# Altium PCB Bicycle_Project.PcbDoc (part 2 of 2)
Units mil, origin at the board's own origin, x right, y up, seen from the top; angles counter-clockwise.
Board outline 2480.32 x 3188.98 mil, 2 copper layers (Top Layer, Bottom Layer), stack 35.085 mil thick; 108 components, 95 nets, 359 pads, 124 vias.

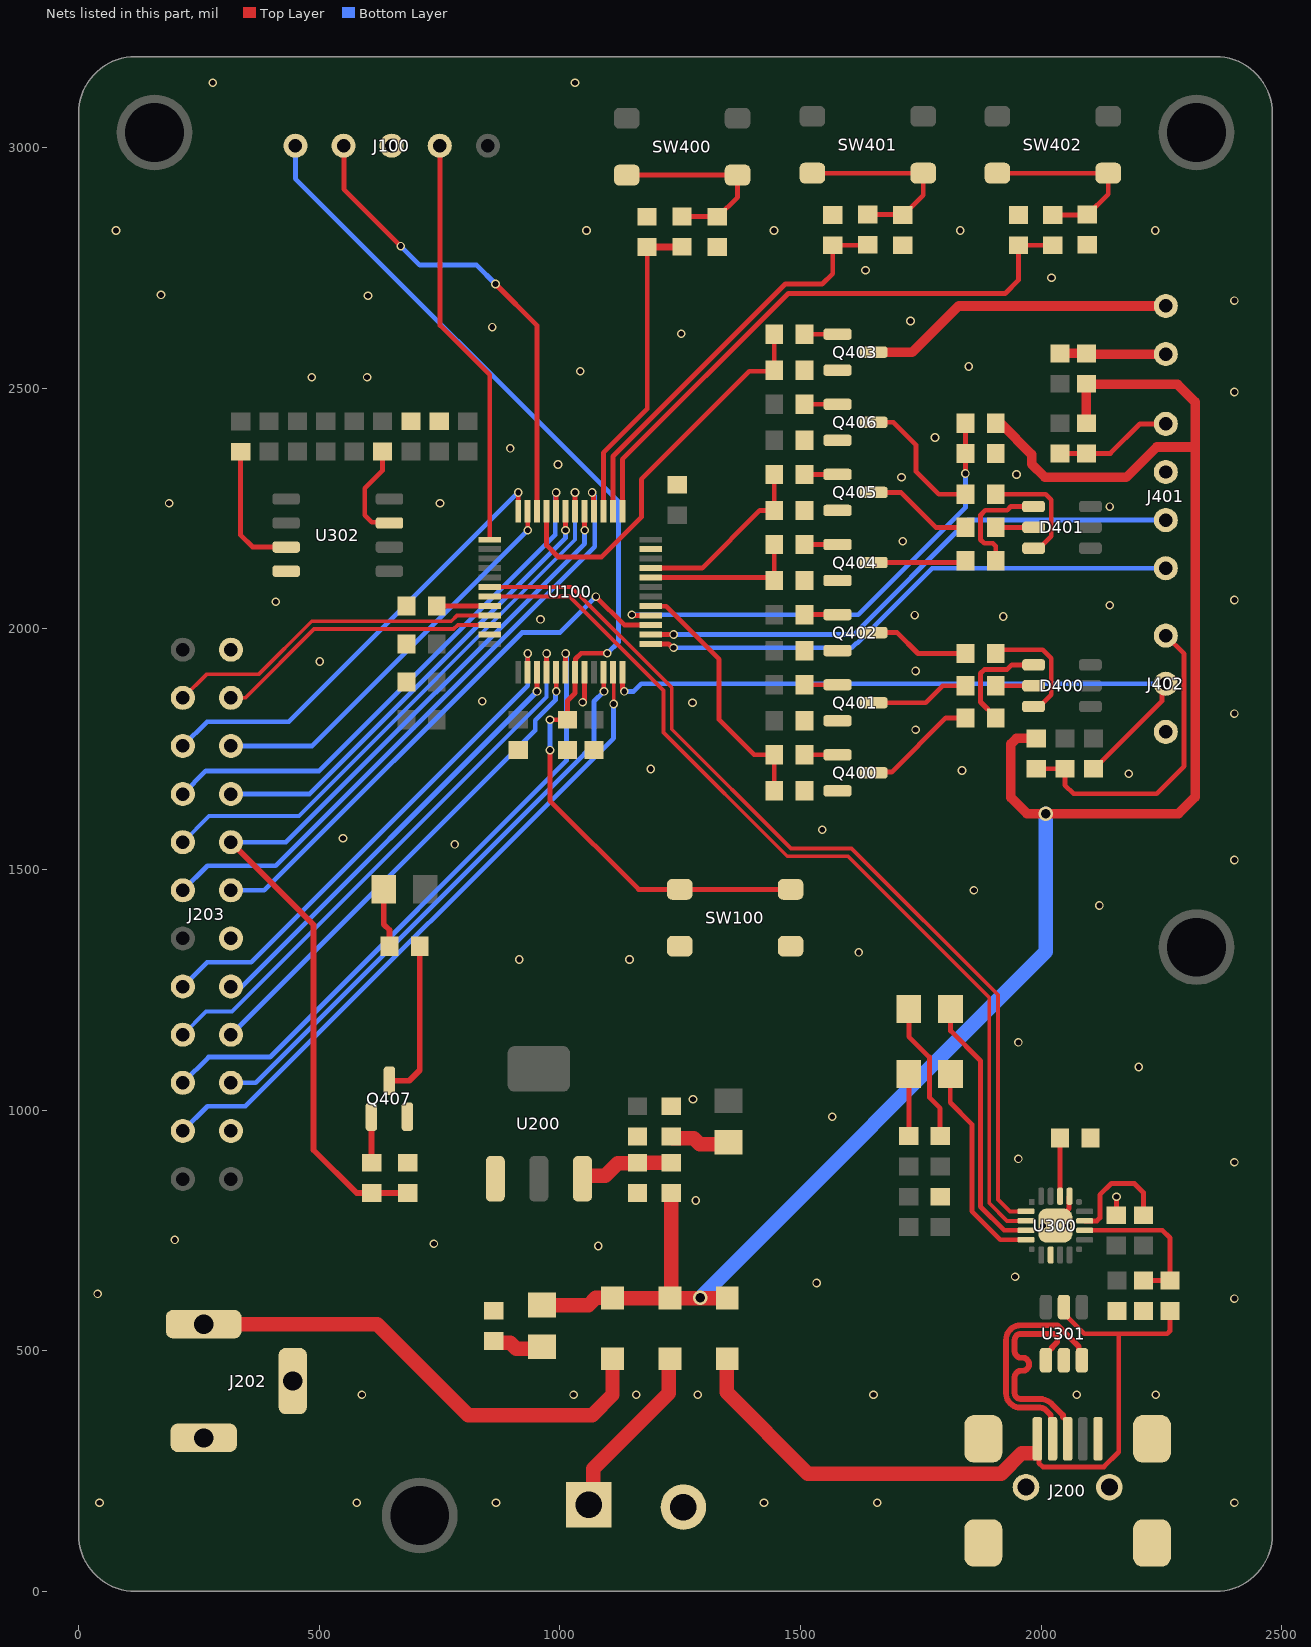
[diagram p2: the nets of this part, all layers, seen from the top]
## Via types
v1: diameter 18, hole 12, Top Layer to Bottom Layer, tented both sides, 122 vias
v2: diameter 30, hole 20, Top Layer to Bottom Layer, tented both sides, 2 vias

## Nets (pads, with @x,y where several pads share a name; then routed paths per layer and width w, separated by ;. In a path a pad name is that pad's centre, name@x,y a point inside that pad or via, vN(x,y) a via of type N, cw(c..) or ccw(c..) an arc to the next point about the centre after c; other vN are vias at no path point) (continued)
G_TEMP_LED: R415.1 R418.2 U100.21 | length 380.9
  Top Layer w10: U100.21@1188.86,2126.26 1295.55,2126.26 1415.26,2245.96 R418.2@1445.39,2245.96 R415.1@1445.39,2320.77
GND: C100.2 C101.2 C102.2 C103.2 C104.2 C105.2 C210.2 C211.2 C300.2 C301.2 C302.2 C303.2 C304.2 C400.1 C401.1 C402.1 J100.3 J200.0 J200.5 J201.2 J202.2 J202.3 J203.3 J203.11 J203.23 J401.2 J402.3 Q400.2 Q401.2 Q402.2 Q403.2 Q404.2 Q405.2 Q406.2 Q407.2 R100.2 R102.1 R200.1 R201.1 R301.2 R305.1 R406.1 R407.1 R408.1 R410.1 R417.1 R418.1 R419.1 R423.1 R424.1 R425.1 R429.1 SW100.2 U100.8 U100.23 U100.47 U200.1 U300.3 U300.12 U300.21 U301.2 U302.4 | length 175.5
  Top Layer w10: v1(1047.24,1847.44) 1047.24,1849.61 1051.06,1853.42 U100.8@1051.06,1909.72 ; U300.21@2029.45,760 2029.45,766.88 2058.07,795.5 2058.07,820.12 U300.12@2058.98,821.02 ; C302.2@2156.2,781.66 2156.5,781.95 v1(2156.5,819.88)
  other v1: 43.31,184.06 577.76,184.06 867.13,184.06 1424.21,184.06 1659.45,184.06 2401.57,184.06 588.58,408.46 1028.54,408.46 1158.46,408.46 1286.42,408.46 1651.57,408.46 2073.82,408.46 2238.19,408.46 2401.57,608.27 39.37,618.11 1533.46,640.75 1945.87,653.54 1079.72,717.52 738.19,722.44 199.8,730.32 2003.94,759.84 2055.12,759.84 1282.48,812.01 2401.57,891.73 1952.76,898.62 1565.94,986.22 1276.57,1022.64 2202.76,1089.57 1952.76,1140.75 915.35,1312.99 1144.68,1312.99 1621.06,1327.76 2121.06,1425.2 1860.24,1456.69 2401.57,1519.68 781.5,1552.17 549.21,1564.96 1545.28,1582.68 2182.09,1698.82 1835.63,1705.71 1188.98,1708.66 1739.17,1790.35 2401.57,1823.82 1275.59,1846.46 838.58,1849.41 1739.17,1912.4 500.98,1932.09 959.65,2019.61 1921.26,2025.59 1737.2,2028.54 2142.72,2049.21 409.45,2056.1 2401.57,2060.04 1712.6,2182.09 2142.72,2253.94 187.99,2260.83 750.98,2260.83 1709.65,2314.96 1948.82,2320.87 996.06,2341.54 896.65,2375 1779.53,2397.64 2401.57,2492.13 484.25,2522.64 599.41,2522.64 1042.32,2535.43 1849.41,2545.28 1251.97,2613.19 859.25,2626.97 1728.35,2639.76 2401.57,2682.09 601.38,2691.93 171.26,2693.9 2021.65,2729.33 1634.84,2745.08 77.76,2827.76 1055.12,2827.76 1444.88,2827.76 1831.69,2827.76 2237.2,2827.76 278.54,3134.84 1031.5,3134.84
LOAD: R409.1 R410.2 U100.33 | length 835.6
  Top Layer w10: U100.33@972.32,2244.37 972.39,2244.3 972.39,2173.28 996.06,2149.61 1086.83,2149.61 1169.29,2232.07 1169.29,2311.02 1393.7,2535.43 1443.43,2535.43 R410.2@1445.39,2537.4 R409.1@1445.39,2612.2
MCU_RX: U100.43 U300.18 | length 1952.9
  Top Layer w8: U100.43@854.21,2067.2 1020.21,2067.2 1215.17,1872.24 1215.17,1784.83 1472.44,1527.56 1598.43,1527.56 1892.02,1233.97 1892.02,807.09 1929.26,769.84 U300.18@1968.43,769.84
MCU_TX: U100.42 U300.17 | length 1951.2
  Top Layer w8: U100.42@854.21,2086.89 1023.15,2086.89 1232.28,1877.76 1232.28,1791.34 1480.06,1543.56 1606.05,1543.56 1910.02,1239.59 1910.02,814.54 1935.03,789.53 U300.17@1968.43,789.53
NetC210_1: C210.1 FB200.2 U200.3 | length 199.3
  Top Layer w30: U200.3@1046.93,857.29 1051.54,861.89 1051.54,863.65 1093.96,863.65 1120.11,889.8 1160.35,889.8 C210.1@1161.3,890.75 FB200.2@1231.3,890.75
NetD201_2: D201.2 R200.2 | length 108.5
  Top Layer w30: R200.2@862.8,520.15 866.3,516.65 896.73,516.65 909.45,503.94 958.54,503.94 D201.2@962.8,508.19
NetD204_2: D204.2 R201.2 | length 127.2
  Top Layer w30: R201.2@1231.3,944.88 1234.8,941.38 1278.11,941.38 1290.35,929.13 1346.46,929.13 D204.2@1350.39,933.07
NetD300_1: D300.1 R302.1 | length 129.1
  Top Layer w10: R302.1@1725.08,945.88 D300.1@1725.08,1075
NetD300_2: D300.2 U300.20 | length 441.2
  Top Layer w10: D300.2@1811.69,1075 1811.02,1074.33 1811.02,1015.75 1856.02,970.76 1856.02,789.65 1915.2,730.47 U300.20@1968.43,730.47
NetD301_1: D301.1 R303.1 | length 291
  Top Layer w10: D301.1@1725.08,1210 1725.08,1152.87 1767.72,1110.24 1767.72,1026.3 1790.08,1003.94 R303.1@1790.08,945.88
NetD301_2: D301.2 U300.19 | length 551.3
  Top Layer w10: D301.2@1811.69,1210 1811.69,1164.69 1874.02,1102.36 1874.02,799.21 1922.88,750.35 1968.23,750.35 U300.19@1968.43,750.16
NetD400_1: D400.1 R400.2 | length 223
  Top Layer w10: R400.2@1905.52,1814.96 1905.52,1816.46 1874.01,1847.96 1874.01,1907.27 1882.56,1915.82 1929.4,1915.82 1938.78,1925.2 D400.1@1984.25,1925.2
NetD400_2: D400.2 R401.2 | length 78.7
  Top Layer w10: R401.2@1905.51,1881.89 D400.2@1984.25,1881.89
NetD400_3: D400.3 R402.2 | length 248.4
  Top Layer w10: R402.2@1905.52,1948.82 1913.39,1956.69 2003.11,1956.69 2020.87,1938.93 2020.87,1863.39 1996.06,1838.58 D400.3@1984.25,1838.58
NetD401_1: D401.1 R411.2 | length 235.8
  Top Layer w10: R411.2@1905.52,2141.73 1905.52,2172.05 1899.66,2177.91 1881.63,2177.91 1874.02,2185.52 1874.02,2236.29 1884.25,2246.53 1929.4,2246.53 1937.09,2254.21 D401.1@1984.25,2254.21
NetD401_2: D401.2 R412.2 | length 78.7
  Top Layer w10: R412.2@1905.52,2210.91 D401.2@1984.25,2210.91
NetD401_3: D401.3 R413.2 | length 242.6
  Top Layer w10: R413.2@1905.52,2279.53 2009.3,2279.53 2020.87,2267.95 2020.87,2192.41 1996.06,2167.6 D401.3@1984.25,2167.6
NetD402_2: D402.2 R427.2 | length 123
  Top Layer w12: D402.2@633.86,1458.66 633.86,1385.83 645.67,1374.02 R427.2@645.67,1340.55
NetFB400_2: FB400.2 FB401.2 J400.2 | length 220.6
  Top Layer w20: FB401.2@2039.02,2572.41 FB400.2@2094.02,2572.41 2095.52,2570.91 J400.2@2259.02,2570.91
NetFB402_2: FB402.2 FB404.2 J402.1 | length 659.3
  Top Layer w10: FB402.2@1989.96,1709.41 FB404.2@2049.49,1709.41 2049.49,1675.47 2067.48,1657.48 2240.16,1657.48 2297.02,1714.34 2297.02,1947.91 J402.1@2259.02,1985.91
NetFB403_2: FB403.2 FB405.2 J401.1 | length 245.5
  Top Layer w10: FB405.2@2039.02,2364.41 FB403.2@2094.02,2364.41 2143.93,2364.41 2205.43,2425.91 J401.1@2259.02,2425.91
NetJ400_1: J400.1 Q403.3 | length 647.2
  Top Layer w20: Q403.3@1651.57,2574.8 1732.28,2574.8 1828.39,2670.91 J400.1@2259.02,2670.91
NetQ400_1: Q400.1 R403.2 | length 70.8
  Top Layer w10: R403.2@1508.39,1738.19 1570.87,1738.19 1573.82,1741.14 Q400.1@1576.77,1738.19
NetQ400_3: Q400.3 R400.1 | length 238.2
  Top Layer w10: Q400.3@1651.57,1700.79 1653.12,1702.33 1689.12,1702.33 1801.75,1814.96 R400.1@1842.52,1814.96
NetQ401_1: Q401.1 R404.2 | length 68.4
  Top Layer w10: R404.2@1508.39,1883.86 Q401.1@1576.77,1883.86
NetQ401_3: Q401.3 R401.1 | length 205.6
  Top Layer w10: Q401.3@1651.57,1846.46 1759.84,1846.46 1795.28,1881.89 R401.1@1842.51,1881.89
NetQ402_1: Q402.1 R405.2 | length 69.2
  Top Layer w10: R405.2@1508.39,2029.53 1574.8,2029.53 1575.79,2030.51 Q402.1@1576.77,2029.53
NetQ402_3: Q402.3 R402.1 | length 208.9
  Top Layer w10: Q402.3@1651.57,1992.13 1700.79,1992.13 1744.09,1948.82 R402.1@1842.52,1948.82
NetQ403_1: Q403.1 R409.2 | length 72.6
  Top Layer w10: R409.2@1508.39,2612.2 1573.82,2612.2 1576.77,2609.25 Q403.1@1576.77,2612.2
NetQ404_1: Q404.1 R414.2 | length 68.5
  Top Layer w10: R414.2@1508.39,2175.39 1508.59,2175.2 Q404.1@1576.77,2175.2
NetQ404_3: Q404.3 R411.1 | length 192.6
  Top Layer w10: Q404.3@1651.57,2137.8 1838.58,2137.8 R411.1@1842.52,2141.73
NetQ405_1: Q405.1 R415.2 | length 68.4
  Top Layer w10: R415.2@1508.39,2320.77 1508.49,2320.87 Q405.1@1576.77,2320.87
NetQ405_3: Q405.3 R412.1 | length 221
  Top Layer w10: Q405.3@1651.57,2283.46 1708.66,2283.46 1781.22,2210.91 R412.1@1842.52,2210.91
NetQ406_1: Q406.1 R416.2 | length 68.4
  Top Layer w10: R416.2@1508.39,2466.54 Q406.1@1576.77,2466.54
NetQ406_3: Q406.3 R413.1 | length 285.2
  Top Layer w10: Q406.3@1651.57,2429.13 1692.91,2429.13 1740.16,2381.89 1740.16,2326.77 1787.4,2279.53 R413.1@1842.52,2279.53
NetQ407_1: Q407.1 R428.2 | length 95.9
  Top Layer w12: Q407.1@608.27,986.22 608.27,891.68 R428.2@609.19,890.75
NetQ407_3: Q407.3 R427.1 | length 329.8
  Top Layer w12: Q407.3@645.67,1061.02 687.01,1061.02 708.67,1082.68 R427.1@708.67,1340.55
NetR100_1: R100.1 U100.44 | length 110.2
  Top Layer w10: R100.1@744.1,2047.24 744.37,2047.52 U100.44@854.21,2047.52
NetR300_2: R300.2 R301.1 U300.8 | length 327.6
  Top Layer w10: U300.8@2090.47,750.16 2251.86,750.16 2267.72,734.3 R300.2@2267.72,645.67 R301.1@2212.6,645.67
NetR304_2: R304.2 U300.9 | length 237.2
  Top Layer w10: U300.9@2090.47,769.84 2115.98,769.84 2122.05,775.91 2122.05,823.82 2145.67,847.44 2193.9,847.44 2212.6,828.74 R304.2@2212.6,781.66
NetR305_2: R305.2 U300.13 | length 120.9
  Top Layer w10: U300.13@2039.29,821.02 R305.2@2039.29,941.93
NetR306_1: R306.1 U302.3 | length 278.1
  Top Layer w10: R306.1@336.61,2368.11 336.61,2194.88 361.22,2170.28 430.67,2170.28 U302.3@431.14,2169.8
NetR309_1: R309.1 U302.7 | length 205.4
  Top Layer w10: R309.1@631.5,2368.3 631.5,2329.33 594.49,2292.32 594.49,2236.22 609.25,2221.46 644.06,2221.46 U302.7@645.71,2219.8
NetR420_1: R420.1 R423.2 SW400.1 | length 408.5
  Top Layer w10: SW400.1@1138.78,2942.91 SW400.1@1369.09,2942.91 1369.09,2897.13 1328.27,2856.3 R423.2@1326.77,2856.3 1326.06,2857.01 R420.1@1253.94,2857.01
NetR421_1: R421.1 R424.2 SW401.1 | length 408.5
  Top Layer w10: SW401.1@1524.61,2946.85 SW401.1@1754.92,2946.85 1754.92,2901.06 1714.1,2860.24 R424.2@1712.6,2860.24 1711.89,2860.95 R421.1@1639.76,2860.95
NetR422_1: R422.1 R425.2 SW402.1 | length 407
  Top Layer w10: SW402.1@1909.09,2946.85 SW402.1@2139.41,2946.85 2139.41,2903.11 2097.25,2860.95 R425.2@2095.75,2860.95 2095.04,2860.24 R422.1@2024.25,2860.24
PA0: J203.5 U100.10 | length 1204.9
  Top Layer w10: U100.10@1090.43,1909.72 1091.09,1909.07 1091.09,1870.74 v1(1091.75,1870.08)
  Bottom Layer w10: J203.5@316.54,1056.69 368.14,1056.69 1027.56,1716.12 1027.56,1716.54 1070.87,1759.84 1070.87,1849.2 v1(1091.75,1870.08)
PA1: J203.4 U100.11 | length 1370.6
  Top Layer w8: U100.11@1110.12,1909.72 1111.75,1908.09 1111.75,1844.03 v1(1111.55,1843.83)
  Bottom Layer w10: J203.4@216.54,956.69 267.72,1007.87 346.46,1007.87 1111.55,1772.97 v1(1111.55,1843.83)
PA5: J203.13 U100.15 | length 1149.4
  Top Layer w10: v1(1074.8,2066.93) 1133.58,2008.15 U100.15@1188.86,2008.15
  Bottom Layer w10: J203.13@316.54,1456.69 385.83,1456.69 921.26,1992.13 1000,1992.13 v1(1074.8,2066.93)
PA9: J203.16 U100.30 | length 1212.8
  Top Layer w10: U100.30@1031.38,2244.37 U100.30@1031.38,2244.37 1031.44,2283.41 v1(1031.5,2283.46)
  Bottom Layer w8: J203.16@216.54,1556.69 270.95,1611.1 457.56,1611.1 1031.5,2185.04 v1(1031.5,2283.46)
PA10: J203.17 U100.31 | length 971.1
  Top Layer w10: v1(1011.5,2204.72) 1011.59,2204.82 1011.59,2244.27 U100.31@1011.69,2244.37
  Bottom Layer w10: J203.17@316.54,1656.69 479.53,1656.69 1011.5,2188.66 v1(1011.5,2204.72)
PA11: J203.18 U100.32 | length 1125.1
  Top Layer w10: U100.32@992.01,2244.37 992.07,2244.43 992.07,2283.41 v1(992.13,2283.46)
  Bottom Layer w10: J203.18@216.54,1656.69 264.57,1704.72 500,1704.72 990.5,2195.22 990.5,2276.18 990.6,2276.28 990.6,2281.93 v1(992.13,2283.46)
PB8: J203.22 U100.45 | length 708.6
  Top Layer w8: J203.22@216.54,1856.69 265.35,1905.51 374.02,1905.51 484.25,2015.75 774.27,2015.75 786.36,2027.83 U100.45@854.21,2027.83
PB9: J203.21 U100.46 | length 600.4
  Top Layer w8: J203.21@316.54,1856.69 346.41,1856.69 489.22,1999.5 779.24,1999.5 787.88,2008.15 U100.46@854.21,2008.15
PB15: J203.14 U100.28 | length 1307.3
  Top Layer w10: v1(1066.93,2283.46) 1066.93,2281.3 1069.75,2278.48 1069.75,2245.37 U100.28@1070.75,2244.37
  Bottom Layer w10: J203.14@216.54,1456.69 267.72,1507.87 409.45,1507.87 1072.5,2170.92 1072.5,2276.18 1066.93,2281.74 v1(1066.93,2283.46)
PB_DOWN: C402.2 R422.2 U100.25 | length 1229.2
  Top Layer w10: U100.25@1129.8,2244.37 1129.8,2352.08 1474.57,2696.85 1925.2,2696.85 1952.76,2724.41 C402.2@1952.76,2797.24 R422.2@2024.25,2797.24
PB_MODE: C401.2 R421.2 U100.26 | length 860.2
  Top Layer w10: U100.26@1110.12,2244.37 1110.12,2358.15 1468.5,2716.54 1545.28,2716.54 1566.93,2738.19 C401.2@1566.93,2797.24 1639.05,2797.24 R421.2@1639.76,2797.95
PB_UP: C400.2 R420.2 U100.27 | length 660.1
  Top Layer w10: U100.27@1090.43,2244.37 1090.43,2366.02 1181.46,2457.05 C400.2@1181.46,2793.66
  Top Layer w15: C400.2@1181.1,2793.3 1181.46,2793.66 1253.58,2793.66 R420.2@1253.94,2794.01
PC13: J203.10 U100.2 | length 1081.6
  Top Layer w10: U100.2@932.95,1909.72 933.01,1909.78 933.01,1948.76 v1(933.07,1948.82)
  Bottom Layer w10: J203.10@216.54,1256.69 266.93,1307.09 358.27,1307.09 933.07,1881.89 v1(933.07,1948.82)
PC14: J203.9 U100.3 | length 929.9
  Top Layer w10: v1(952.44,1870.08) 952.54,1870.18 952.54,1909.63 U100.3@952.64,1909.72
  Bottom Layer w10: J203.9@316.54,1256.69 339.37,1256.69 952.44,1869.76 v1(952.44,1870.08)
PC15: J203.8 U100.4 | length 1176.2
  Top Layer w10: U100.4@972.32,1909.72 972.38,1909.78 v1(972.44,1948.82) v1(972.44,1948.82)
  Bottom Layer w8: J203.8@216.54,1156.69 264.57,1204.72 318.9,1204.72 972.44,1858.27 v1(972.44,1948.82)
PF0: J203.7 U100.5 | length 1033.2
  Top Layer w10: U100.5@992.01,1909.72 992.22,1909.51 992.22,1870.3 v1(992.44,1870.08)
  Bottom Layer w10: J203.7@316.54,1156.69 948.82,1788.98 948.82,1810.21 990.91,1852.3 990.91,1868.55 v1(992.44,1870.08)
PF1: J203.6 U100.6 | length 1336.8
  Top Layer w10: U100.6@1011.69,1909.72 1011.75,1909.78 v1(1011.81,1948.82) v1(1011.81,1948.82)
  Bottom Layer w10: J203.6@216.54,1056.69 270.08,1110.24 397.64,1110.24 1013.44,1726.04 1013.44,1941.53 1013.34,1941.63 1013.34,1947.29 v1(1011.81,1948.82)
PF6: J203.19 U100.35 | length 841.8
  Top Layer w10: U100.35@932.95,2244.37 933.01,2244.31 933.01,2204.78 v1(933.07,2204.72)
  Bottom Layer w10: J203.19@316.54,1756.69 485.04,1756.69 v1(933.07,2204.72)
PF7: J203.20 U100.36 | length 954.2
  Top Layer w10: U100.36@913.27,2244.37 U100.36@913.27,2244.37 913.33,2283.41 v1(913.39,2283.46)
  Bottom Layer w10: J203.20@216.54,1756.69 266.93,1807.09 437.01,1807.09 v1(913.39,2283.46)
POWER_INPUT_MEASURE: R101.1 R102.2 U100.16 | length 1000.4
  Top Layer w10: v1(1149.61,2029.15) 1150.92,2027.83 U100.16@1188.86,2027.83 ; v1(1842.52,2322.83) R102.2@1842.52,2364.41 R101.1@1842.52,2427.41
  Bottom Layer w10: v1(1149.61,2029.15) 1619.7,2029.15 1842.52,2251.97 v1(1842.52,2322.83)
R_SPEED_LED: R403.1 R406.2 U100.17 | length 533.3
  Top Layer w10: U100.17@1188.86,2047.52 1189.54,2046.83 1220.88,2046.83 1330.71,1937.01 1330.71,1811.02 1403.54,1738.19 R403.1@1445.39,1738.19 R406.2@1445.39,1663.39
R_TEMP_LED: R414.1 R417.2 U100.20 | length 334.1
  Top Layer w10: U100.20@1188.86,2106.57 1439.21,2106.57 R417.2@1445.39,2100.39 R414.1@1445.39,2175.39
RESET_MCU: C105.1 J100.5 SW100.1 U100.7 | length 2328.1
  Top Layer w10: v1(979.33,1748.02) 979.33,1642.72 1163.39,1458.66 SW100.1@1249.02,1458.66 SW100.1@1479.33,1458.66 ; v1(979.33,1811.02) C105.1@1015.75,1811.02 1015.75,1850.4 1031.38,1866.03 U100.7@1031.38,1909.72 1032.38,1910.72 1032.38,1937.51 1044.09,1949.22 1098.33,1949.22 v1(1098.46,1949.1)
  Bottom Layer w10: J100.5@450.39,3003.94 450.39,2935.43 1122.05,2263.78 1122.05,1972.68 v1(1098.46,1949.1) ; v1(979.33,1748.02) v1(979.33,1811.02)
SETTING_LED: J203.15 R428.1 R429.2 U100.29 | length 2002.5
  Top Layer w10: U100.29@1051.06,2244.37 1051.28,2244.15 1051.28,2204.94 v1(1051.5,2204.72)
  Top Layer w12: J203.15@316.54,1556.69 488.19,1385.04 488.19,917.32 577.76,827.75 R428.1@609.19,827.75 R429.2@684,827.75
  Bottom Layer w10: J203.15@316.54,1556.69 430.71,1556.69 1051.18,2177.17 1051.18,2204.41 v1(1051.5,2204.72)
SPEED_SENSOR_ANALOG_PIN: J401.4 U100.13 | length 1142.1
  Top Layer w10: U100.13@1188.86,1968.78 1189.13,1968.5 1226.18,1968.5 1234.06,1960.63 v1(1236.22,1960.63)
  Bottom Layer w10: v1(1236.22,1960.63) 1606.3,1960.63 1615.86,1970.19 1617.69,1970.19 1773.49,2125.98 2258.94,2125.98 J401.4@2259.02,2125.91
SPEED_SENSOR_DIGITAL_PIN: J401.3 U100.14 | length 1168.7
  Top Layer w10: U100.14@1188.86,1988.46 1189,1988.33 1236.08,1988.33 v1(1236.22,1988.19)
  Bottom Layer w10: v1(1236.22,1988.19) 1610.24,1988.19 1847.95,2225.91 J401.3@2259.02,2225.91
SYS_SWCLK: J100.2 U100.37 | length 861.3
  Top Layer w10: J100.2@751.18,3003.94 751.18,2630.6 854.21,2527.57 U100.37@854.21,2185.32
SYS_SWDIO: J100.4 U100.34 | length 995
  Top Layer w10: J100.4@551.18,3003.94 551.18,2913.39 v1(669.29,2795.28) ; v1(866.14,2716.54) 952.64,2630.04 U100.34@952.64,2244.37
  Bottom Layer w10: v1(669.29,2795.28) 708.66,2755.91 826.77,2755.91 v1(866.14,2716.54)
TEMPERATURE_SENSOR: J402.2 R426.2 U100.12 | length 1412.5
  Top Layer w10: U100.12@1129.8,1909.72 1130.19,1909.33 1130.19,1875.91 1133.86,1872.24 v1(1133.86,1870.08) ; R426.2@2109.02,1709.41 2110.52,1709.41 2251.36,1850.25 2251.36,1878.25 J402.2@2259.02,1885.91
  Bottom Layer w10: v1(1133.86,1870.08) 1153.54,1870.08 1169.37,1885.91 J402.2@2259.02,1885.91
USB_D_N: J200.2 U301.3 | length 495.2
  Top Layer w12: 2009.47,376.67 ccw(c1996.88,364.08) 1996.88,381.89 1956.85,381.89 cw(c1956.85,411.81) 1935.69,390.65 1935.63,390.72 cw(c1956.75,411.83) 1926.88,411.83 1926.88,521.99 cw(c1958.32,521.99) 1936.09,544.22 1936.15,544.28 cw(c1957.1,523.34) 1957.1,552.96 2033.74,552.96 2078.1,508.6 2078.1,486.86 U301.3@2084.65,480.32 ; 2009.47,376.67 2019.89,366.26 2019.89,320.66 J200.2@2023.62,316.93
USB_D_P: J200.3 U301.1 | length 476.2
  Top Layer w12: U301.1@2009.84,480.32 2009.84,493.33 2022.45,505.93 2022.45,507.13 2033.31,517.99 2033.31,527.93 2026.28,534.96 1957.18,534.96 ccw(c1957.18,523.13) 1948.82,531.5 ccw(c1958.32,521.99) 1944.88,521.99 1944.88,521.55 1944.88,498.89 ccw(c1958.38,498.89) 1958.38,485.39 1961.38,485.39 cw(c1961.38,471.89) 1961.38,458.39 1958.38,458.39 ccw(c1958.38,444.89) 1944.88,444.89 1944.88,411.89 ccw(c1956.88,411.89) 1948.4,403.4 ccw(c1956.88,411.89) 1956.88,399.89 1996.88,399.89 cw(c1996.88,364.08) 2022.18,389.42 2045.44,366.16 2045.46,362.02 2055.12,352.36 J200.3@2055.12,316.93
VIN: D200.1 D201.1 D202.1 D203.1 FB200.1 FB400.1 FB402.1 FB403.1 R101.2 | length 4120
  Top Layer w20: R101.2@1905.52,2427.41 1907.72,2425.2 1917.42,2425.2 1980.32,2362.3 1980.32,2342.52 2007.87,2314.96 2177.17,2314.96 2240.16,2377.95 2320.02,2377.95 ; FB402.1@1989.96,1772.41 1948.72,1772.41 1937.01,1760.69 1937.01,1649.61 1970.53,1616.09 v2(2009.9,1616.09) 2285.47,1616.09 2320.02,1650.63 2320.02,2377.95 ; FB403.1@2094.02,2427.41 2094.02,2506.34 2095.55,2507.87 2283.46,2507.87 2320.02,2471.32 2320.02,2377.95
  Top Layer w30: D201.1@962.8,594.8 1059.37,594.8 1074.8,610.24 1108.56,610.24 D200.1@1109.31,609.49 D203.1@1228.55,609.49 1290.59,609.49 v2(1291.34,610.24) 1292.09,609.49 D202.1@1347.8,609.49 ; D203.1@1231.3,615.9 FB200.1@1231.3,819.88
  Bottom Layer w30: v2(1291.34,610.24) 2009.9,1328.8 v2(2009.9,1616.09)
VIN_BORNER: D203.2 J201.1 | length 373.4
  Top Layer w30: J201.1@1059.79,180 1069.63,189.84 1069.63,254.67 1226.26,411.29 1226.26,481.21 D203.2@1228.55,483.5
VIN_POWER_JACK: D200.2 J202.1 | length 1020.3
  Top Layer w30: J202.1@259.84,555.12 620.45,555.12 809.43,366.14 1066.93,366.14 1109.31,408.52 D200.2@1109.31,483.5
VIN_USB: D202.2 J200.1 R300.1 U301.5 | length 1605.1
  Top Layer w10: J200.1@1996.97,286.66 1996.97,312.09 J200.1@1992.13,316.93 1992.13,312.09 1992.13,286.66 1995.23,283.56 1995.23,266.58 2003.16,258.65 2130.45,258.65 2161.42,289.62 2161.42,535.43 ; U301.5@2047.24,590.55 2047.24,577.76 2089.56,535.43 2161.42,535.43 ; R300.1@2267.72,582.67 2267.72,541.29 2261.86,535.43 2161.42,535.43
  Top Layer w30: D202.2@1347.8,483.5 1346.46,482.17 1346.46,413.39 1515.13,244.72 1917.29,244.72 1959.23,286.66 J200.1@1986.97,286.66
pads on no net: J200.4 U200.4 U300.1 U300.2 U300.10 U300.11 U300.14 U300.15 U300.16
copper on no net:
  other v1: 1003.94,1055.12 909.45,1114.17

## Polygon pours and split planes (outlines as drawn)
GND on Top Layer "GND_TOP" (solid, remove dead copper, pour order 3): 0,118.11 0,3070.87 cw(c118.11,3070.87) 118.11,3188.98 2362.2,3188.98 cw(c2362.2,3070.87) 2480.32,3070.87 2480.32,118.11 cw(c2362.2,118.11) 2362.2,0 118.11,0 cw(c118.11,118.11)
GND on Bottom Layer "GND_BOT" (solid, remove dead copper, pour order 9): 0,118.11 0,3070.87 cw(c118.11,3070.87) 118.11,3188.98 2362.2,3188.98 cw(c2362.2,3070.87) 2480.32,3070.87 2480.32,118.11 cw(c2362.2,118.11) 2362.2,0 118.11,0 cw(c118.11,118.11)

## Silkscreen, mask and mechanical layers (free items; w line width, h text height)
Top Overlay:
  lines w5: 1659.45,1657.48 1653.54,1663.39 ; 1659.45,1669.29 1653.54,1663.39 ; 1659.45,1805.12 1653.54,1811.02 ; 1659.45,1816.93 1653.54,1811.02 ; 1659.45,1952.76 1653.54,1958.66 ; 1659.45,1964.57 1653.54,1958.66 ; 1659.45,2100.39 1653.54,2106.3 ; 1659.45,2112.2 1653.54,2106.3 ; 1659.45,2238.19 1653.54,2244.09 ; 1659.45,2250 1653.54,2244.09 ; 1659.45,2385.83 1653.54,2391.73 ; 1659.45,2397.64 1653.54,2391.73 ; 1659.45,2529.53 1653.54,2535.43 ; 1659.45,2541.34 1653.54,2535.43 ; 1692.91,1633.86 1830.71,1633.86 1830.71,1334.65 1692.91,1334.65 1692.91,2535.43 1653.54,2535.43 ; 1692.91,1663.39 1653.54,1663.39 ; 1692.91,1811.02 1653.54,1811.02 ; 1692.91,1958.66 1653.54,1958.66 ; 1692.91,2106.3 1653.54,2106.3 ; 1692.91,2244.09 1653.54,2244.09 ; 1692.91,2391.73 1653.54,2391.73
  text "PROGRAMING PORT" at 867.82,3152.48 h30 r180
  text "RST" at 470.59,2842.14 h30 r90
  text "GND" at 667.44,2842.14 h30 r90
  text "3V3" at 868.23,2842.14 h30 r90
  text "SWDIO" at 565.08,2787.15 h30 r90
  text "SWCLK" at 765.87,2782.16 h30 r90
  text "-" at 2355.39,2659.3 h30
  text "+" at 2356.38,2555.12 h30
  text "VCC" at 2347.52,2410.51 h30
  text "Guard" at 222.28,2356.46 h60 r90
  text "GND" at 2347.52,2312.09 h30
  text "DO" at 2347.52,2213.66 h30
  text "ThermoWheel" at 135.67,2195.04 h60 r90
  text "AO" at 2347.52,2115.24 h30
  text "I_SPEED" at 1947.28,2100.55 h30
  text "I_TEMP" at 1962.27,2006.06 h30
  text "VCC" at 2347.52,1969.57 h30
  text "3V3" at 74.22,1942.01 h30
  text "GND" at 386.89,1942.01 h30
  text "DQ" at 2347.52,1869.17 h30
  text "PB8" at 74.22,1841.88 h30
  text "PB9" at 386.89,1841.88 h30
  text "GND" at 2347.52,1768.78 h30
  text "SDA2" at 36.5,1745.16 h30
  text "SCL2" at 386.89,1741.76 h30
  text "PA11" at 52.47,1660.51 h30
  text "PA10" at 386.89,1641.63 h30
  text "~" at 86.69,1613.05 h30
  text "PA9" at 74.22,1541.51 h30
  text "PA8" at 386.89,1541.51 h30
  text "SETTING" at 579.7,1514.76 h30
  text "PA5" at 388.8,1445.32 h30
  text "PB15" at 49.23,1441.38 h30
  text "3V3" at 74.22,1341.26 h30
  text "GND" at 386.89,1341.26 h30
  text "PC13" at 398.7,1245.16 h30
  text "PC13" at 50.28,1242.2 h30
  text "MCU_TX" at 1863.27,1196.17 h30
  text "PC15" at 48.31,1142.8 h30
  text "PF0" at 394.76,1142.8 h30
  text "POWER" at 1277.1,1114.17 h30
  text "PA0" at 392.8,1070.94 h30
  text "3V3" at 1307.09,1070.87 h30
  text "MCU_RX" at 1863.27,1058.37 h30
  text "PF1" at 75.87,1040.43 h30
  text "A0" at 406.57,1030.59 h30
  text "PA1" at 73.9,952.83 h30
  text "GND" at 386.89,940.76 h30
  text "A1" at 92.6,910.51 h30
  text "3V3" at 74.22,840.63 h30
  text "3V3" at 386.89,840.63 h30
  text "POWER" at 890.65,686.1 h30
  text "VIN" at 923.14,642.8 h30
  text "+" at 1043.13,356 h50
  text "-" at 1239.98,356 h50
  text "JACK - 5V" at 61.93,183.53 h30 r90
  text "USB_PORT" at 1812.84,64.06 h30 r90
  text "BORNER - 5V" at 947.76,16.81 h30 r90
Bottom Overlay:
  drawing of 902 lines, arcs and shapes, not listed
  text "J400" at 825.71,2717.6 h30
  text "J100" at 1635.02,2709.72 h30
  text "(I/O=PA12)" at 829.65,2628.11 h30
  text "LOAD" at 971.38,2628.11 h30
  text "Programming Port" at 1809.96,2625.23 h30
  text "-" at 599.49,2542.17 h30
  text "3V3" at 1924.13,2540.43 h30
  text "+" at 827.83,2539.37 h30
  text "RST" at 1309.96,2536.5 h30
  text "SWDIO" at 1487.13,2536.5 h30
  text "GND" at 1609.17,2536.5 h30
  text "SWDLK" at 1798.15,2536.5 h30
  text "GND" at 652.48,2469.57 h30
  text "5V / 3V3" at 952.79,2469.57 h30
  text "NRST" at 1325.71,2465.63 h30
  text "PA13" at 1472.13,2465.63 h30
  text "GND" at 1613.11,2465.63 h30
  text "PA14" at 1780.66,2465.63 h30
  text "3V3" at 1928.07,2465.63 h30
  text "J402" at 825.71,2351.46 h30
  text "J401" at 1632.52,2347.52 h30
  text "Speed Encoder Module" at 1874.94,2266.97 h30
  text "Sensor DS18B20" at 983.19,2264.84 h30
  text "VCC" at 664.12,2178.23 h30
  text "DQ" at 865.83,2178.23 h30
  text "GND" at 1030.43,2178.23 h30
  text "VCC" at 1412.15,2177.24 h30
  text "GND" at 1633.78,2177.24 h30
  text "DO" at 1761.5,2177.24 h30
  text "A0" at 1900.28,2177.24 h30
  text "PA2" at 880.83,2107.36 h30
  text "GND" at 1030.43,2107.36 h30
  text "5V / 3V3" at 739.09,2103.43 h30
  text "5V / 3V3" at 1487.13,2103.43 h30
  text "GND" at 1633.78,2103.43 h30
  text "PA4" at 1776.5,2103.43 h30
  text "PA3" at 1915.28,2103.43 h30
  text "LEDs" at 1637.52,1961.12 h30
  text "PUSH BUTTONS" at 945.67,1957.76 h30
  text "Function" at 1105.24,1902.64 h30
  text "GPIO" at 1347.36,1902.07 h30
  text "Function" at 1989.09,1902.07 h30
  text "Designator" at 857.2,1900.82 h30
  text "Designator" at 1741.06,1900.25 h30
  text "GPIO" at 550.12,1898.7 h30
  text "PB2" at 1262.72,1835.71 h30
  text "PB14" at 550.12,1833.39 h30
  text "SW400" at 789.73,1833.39 h30
  text "RED" at 1412.1,1833.25 h30
  text "UP" at 1022.39,1829.45 h30
  text "I_TEMP" at 1961.6,1773.21 h30
  text "PB10" at 1275.21,1768.8 h30
  text "GREEN" at 1442.09,1768.8 h30
  text "D400" at 1658.59,1769.37 h30
  text "PB13" at 550.12,1766.32 h30
  text "SW401" at 784.73,1766.32 h30
  text "OK/MODE" at 1097.36,1764.84 h30
  text "PB11" at 1270.21,1704.35 h30
  text "BLUE" at 1427.1,1704.35 h30
  text "PB12" at 550.12,1703.33 h30
  text "SW402" at 789.73,1703.33 h30
  text "DOWN" at 1052.38,1699.39 h30
  text "PA7" at 1262.72,1640.33 h30
  text "RED" at 1412.1,1640.33 h30
  text "I_SPEED" at 1976.6,1584.23 h30
  text "D401" at 1653.59,1580.39 h30
  text "PB0" at 1262.72,1575.89 h30
  text "GREEN" at 1442.09,1575.89 h30
  text "PB1" at 1257.72,1511.44 h30
  text "BLUE" at 1427.1,1511.44 h30
  text "Edward  F. Goyeneche" at 85.86,1107.36 h30 r270
  text "Gustavo A. Pisso" at 40.43,1103.43 h30 r270
Board Shape:
  the board outline again, w10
